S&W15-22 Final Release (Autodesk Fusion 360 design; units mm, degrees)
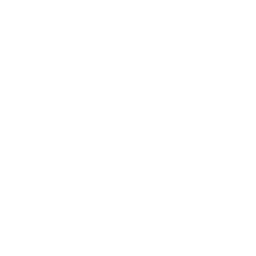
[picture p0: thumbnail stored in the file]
named bodies: "Locking Plate", "Left", "Right"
